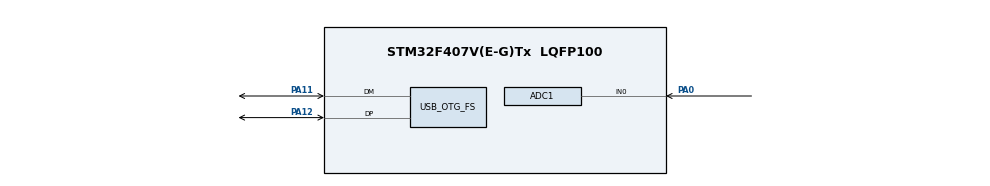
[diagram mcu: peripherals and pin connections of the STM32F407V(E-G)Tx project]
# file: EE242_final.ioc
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ADC1.Channel-0\#ChannelRegularConversion=ADC_CHANNEL_0
ADC1.ContinuousConvMode=ENABLE
ADC1.NbrOfConversionFlag=1
ADC1.Rank-0\#ChannelRegularConversion=1
ADC1.SamplingTime-0\#ChannelRegularConversion=ADC_SAMPLETIME_15CYCLES
ADC1.master=1
Mcu.Family=STM32F4
Mcu.Name=STM32F407V(E-G)Tx
Mcu.Package=LQFP100
NVIC.OTG_FS_IRQn=true\:0\:0\:false\:false\:true\:false\:true\:true
NVIC.PriorityGroup=NVIC_PRIORITYGROUP_4
PA0-WKUP.Signal=ADCx_IN0
PA11.Mode=Device_Only
PA11.Signal=USB_OTG_FS_DM
PA12.Mode=Device_Only
PA12.Signal=USB_OTG_FS_DP
PA13.Mode=Serial_Wire
PA13.Signal=SYS_JTMS-SWDIO
PA14.Mode=Serial_Wire
PA14.Signal=SYS_JTCK-SWCLK
PH0-OSC_IN.Mode=HSE-External-Oscillator
PH0-OSC_IN.Signal=RCC_OSC_IN
PH1-OSC_OUT.Mode=HSE-External-Oscillator
PH1-OSC_OUT.Signal=RCC_OSC_OUT
ProjectManager.HeapSize=0x200
ProjectManager.StackSize=0x400
ProjectManager.TargetToolchain=STM32CubeIDE
RCC.48MHZClocksFreq_Value=48000000
RCC.AHBFreq_Value=72000000
RCC.APB1CLKDivider=RCC_HCLK_DIV2
RCC.APB1Freq_Value=36000000
RCC.APB1TimFreq_Value=72000000
RCC.APB2Freq_Value=72000000
RCC.APB2TimFreq_Value=72000000
RCC.CortexFreq_Value=72000000
RCC.HCLKFreq_Value=72000000
RCC.HSE_VALUE=8000000
RCC.HSI_VALUE=16000000
RCC.LSE_VALUE=32768
RCC.PLLM=4
RCC.PLLN=72
RCC.PLLQ=3
RCC.SYSCLKFreq_VALUE=72000000
RCC.SYSCLKSource=RCC_SYSCLKSOURCE_PLLCLK
RCC.VCOOutputFreq_Value=144000000
SH.ADCx_IN0.0=ADC1_IN0,IN0
USB_DEVICE.CLASS_NAME_FS=CDC
USB_DEVICE.PRODUCT_STRING_CDC_FS=STM32 ComPort
USB_DEVICE.VirtualMode-CDC_FS=Cdc
USB_DEVICE.VirtualModeFS=Cdc_FS
USB_OTG_FS.VirtualMode=Device_Only
VP_USB_DEVICE_VS_USB_DEVICE_CDC_FS.Mode=CDC_FS
board=custom

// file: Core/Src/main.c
#include "main.h"
#include "usb_device.h"
#include "usbd_cdc_if.h"
#include "string.h"
#define LOG_INTERVAL_MS 1000 // Loglama aralığı (milisaniye cinsinden)
#define FLICKER_INTERVAL_MS 16 // Flicker ölçüm aralığı (milisaniye cinsinden)
#define NUM_SAMPLES 60 // Örnekleme sayısı (örneğin, 1 saniyede 60 örnek)

char *data = "\n";

uint16_t adc_value;
float Vadc;

uint8_t buffer[64];

uint16_t flicker_samples[NUM_SAMPLES];
uint8_t flicker_buffer[64];

ADC_HandleTypeDef hadc1;

void SystemClock_Config(void);
static void MX_GPIO_Init(void);
static void MX_ADC1_Init(void);

void Read_ADC(){
	HAL_ADC_Start(&hadc1);
	if(HAL_ADC_PollForConversion(&hadc1,10)== HAL_OK){
		adc_value = HAL_ADC_GetValue(&hadc1);
		Vadc = 3.3 * adc_value/4095;
	}

	HAL_ADC_Stop(&hadc1);
}

void Log_ADC_Data() {
    static uint32_t previous_time = 0;
    uint32_t current_time = HAL_GetTick();
    if (current_time - previous_time >= LOG_INTERVAL_MS) {
        previous_time = current_time;

        Read_ADC();

        // Log verisini oluştur
        snprintf((char*)buffer, sizeof(buffer), "ADC Value: %hu, Voltage: %.2fV\n", adc_value, Vadc);

        // Log verisini USB üzerinden gönder
        CDC_Transmit_FS(buffer, strlen((char*)buffer));
    }
}
void Read_Flicker() {
    static uint8_t sample_index = 0;
    static uint32_t previous_time = 0;
    uint32_t current_time = HAL_GetTick();

    if (current_time - previous_time >= FLICKER_INTERVAL_MS) {
        previous_time = current_time;

        HAL_ADC_Start(&hadc1); // ADC dönüşümünü başlat

        // Fotodiyot veya fotosel değerini oku
        if (HAL_ADC_PollForConversion(&hadc1, 10) == HAL_OK) {
            uint16_t flicker_value = HAL_ADC_GetValue(&hadc1);
            flicker_samples[sample_index] = flicker_value;
        }

        HAL_ADC_Stop(&hadc1); // ADC dönüşümünü durdur

        sample_index++;
        if (sample_index >= NUM_SAMPLES) {
            // Örnekleme tamamlandı, flicker değerini hesapla ve gönder
            float flicker_average = 0.0;
            for (uint8_t i = 0; i < NUM_SAMPLES; i++) {
                flicker_average += flicker_samples[i];
            }
            flicker_average /= NUM_SAMPLES;

            // Flicker değerini tampona formatla
            snprintf((char*)flicker_buffer, sizeof(flicker_buffer), "Flicker: %.2f\n", flicker_average);
            // Flicker değerini USB üzerinden gönder
            CDC_Transmit_FS(flicker_buffer, strlen((char*)flicker_buffer));

            sample_index = 0; // Bir sonraki örnekleme için örnekleyici indeksini sıfırla
        }
    }
}

int main(void)
{

  HAL_Init();

  SystemClock_Config();

  MX_GPIO_Init();
  MX_ADC1_Init();
  MX_USB_DEVICE_Init();

  while (1)
  {
	  CDC_Transmit_FS((uint8_t *)data, strlen(data));
	  HAL_Delay (500);
	  Read_ADC();
	  Log_ADC_Data();
	  Read_Flicker();
  }

}

void SystemClock_Config(void)
{
  RCC_OscInitTypeDef RCC_OscInitStruct = {0};
  RCC_ClkInitTypeDef RCC_ClkInitStruct = {0};

  /** Configure the main internal regulator output voltage
  */
  __HAL_RCC_PWR_CLK_ENABLE();
  __HAL_PWR_VOLTAGESCALING_CONFIG(PWR_REGULATOR_VOLTAGE_SCALE1);

  /** Initializes the RCC Oscillators according to the specified parameters
  * in the RCC_OscInitTypeDef structure.
  */
  RCC_OscInitStruct.OscillatorType = RCC_OSCILLATORTYPE_HSI;
  RCC_OscInitStruct.HSIState = RCC_HSI_ON;
  RCC_OscInitStruct.HSICalibrationValue = RCC_HSICALIBRATION_DEFAULT;
  RCC_OscInitStruct.PLL.PLLState = RCC_PLL_ON;
  RCC_OscInitStruct.PLL.PLLSource = RCC_PLLSOURCE_HSI;
  RCC_OscInitStruct.PLL.PLLM = 16;
  RCC_OscInitStruct.PLL.PLLN = 192;
  RCC_OscInitStruct.PLL.PLLP = RCC_PLLP_DIV2;
  RCC_OscInitStruct.PLL.PLLQ = 4;
  if (HAL_RCC_OscConfig(&RCC_OscInitStruct) != HAL_OK)
  {
    Error_Handler();
  }

  /** Initializes the CPU, AHB and APB buses clocks
  */
  RCC_ClkInitStruct.ClockType = RCC_CLOCKTYPE_HCLK|RCC_CLOCKTYPE_SYSCLK
                              |RCC_CLOCKTYPE_PCLK1|RCC_CLOCKTYPE_PCLK2;
  RCC_ClkInitStruct.SYSCLKSource = RCC_SYSCLKSOURCE_HSI;
  RCC_ClkInitStruct.AHBCLKDivider = RCC_SYSCLK_DIV1;
  RCC_ClkInitStruct.APB1CLKDivider = RCC_HCLK_DIV1;
  RCC_ClkInitStruct.APB2CLKDivider = RCC_HCLK_DIV1;

  if (HAL_RCC_ClockConfig(&RCC_ClkInitStruct, FLASH_LATENCY_0) != HAL_OK)
  {
    Error_Handler();
  }
}

static void MX_ADC1_Init(void)
{

  ADC_ChannelConfTypeDef sConfig = {0};

  /** Configure the global features of the ADC (Clock, Resolution, Data Alignment and number of conversion)
  */
  hadc1.Instance = ADC1;
  hadc1.Init.ClockPrescaler = ADC_CLOCK_SYNC_PCLK_DIV2;
  hadc1.Init.Resolution = ADC_RESOLUTION_12B;
  hadc1.Init.ScanConvMode = DISABLE;
  hadc1.Init.ContinuousConvMode = ENABLE;
  hadc1.Init.DiscontinuousConvMode = DISABLE;
  hadc1.Init.ExternalTrigConvEdge = ADC_EXTERNALTRIGCONVEDGE_NONE;
  hadc1.Init.ExternalTrigConv = ADC_SOFTWARE_START;
  hadc1.Init.DataAlign = ADC_DATAALIGN_RIGHT;
  hadc1.Init.NbrOfConversion = 1;
  hadc1.Init.DMAContinuousRequests = DISABLE;
  hadc1.Init.EOCSelection = ADC_EOC_SINGLE_CONV;
  if (HAL_ADC_Init(&hadc1) != HAL_OK)
  {
    Error_Handler();
  }

  /** Configure for the selected ADC regular channel its corresponding rank in the sequencer and its sample time.
  */
  sConfig.Channel = ADC_CHANNEL_0;
  sConfig.Rank = 1;
  sConfig.SamplingTime = ADC_SAMPLETIME_3CYCLES;
  if (HAL_ADC_ConfigChannel(&hadc1, &sConfig) != HAL_OK)
  {
    Error_Handler();
  }

}

static void MX_GPIO_Init(void)
{

  /* GPIO Ports Clock Enable */
  __HAL_RCC_GPIOH_CLK_ENABLE();
  __HAL_RCC_GPIOA_CLK_ENABLE();

}

void Error_Handler(void)
{
  __disable_irq();
  while (1)
  {
  }
}
